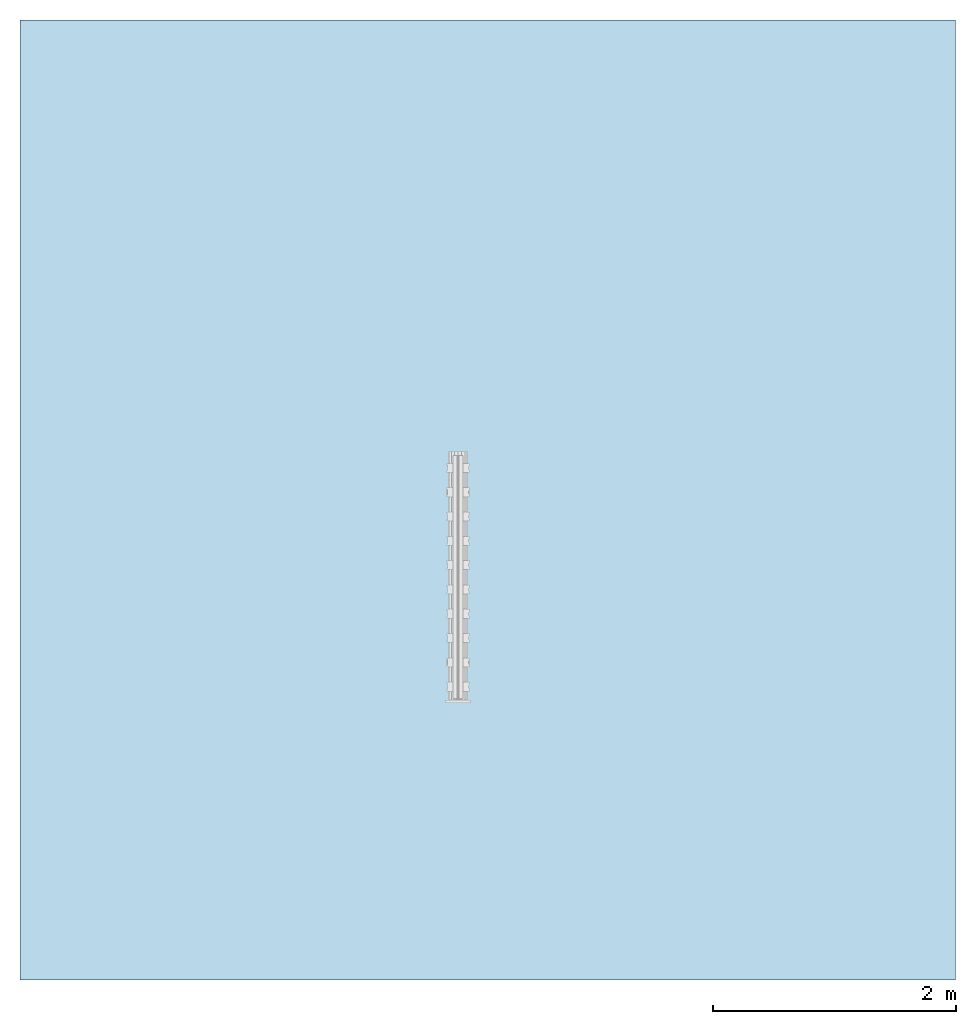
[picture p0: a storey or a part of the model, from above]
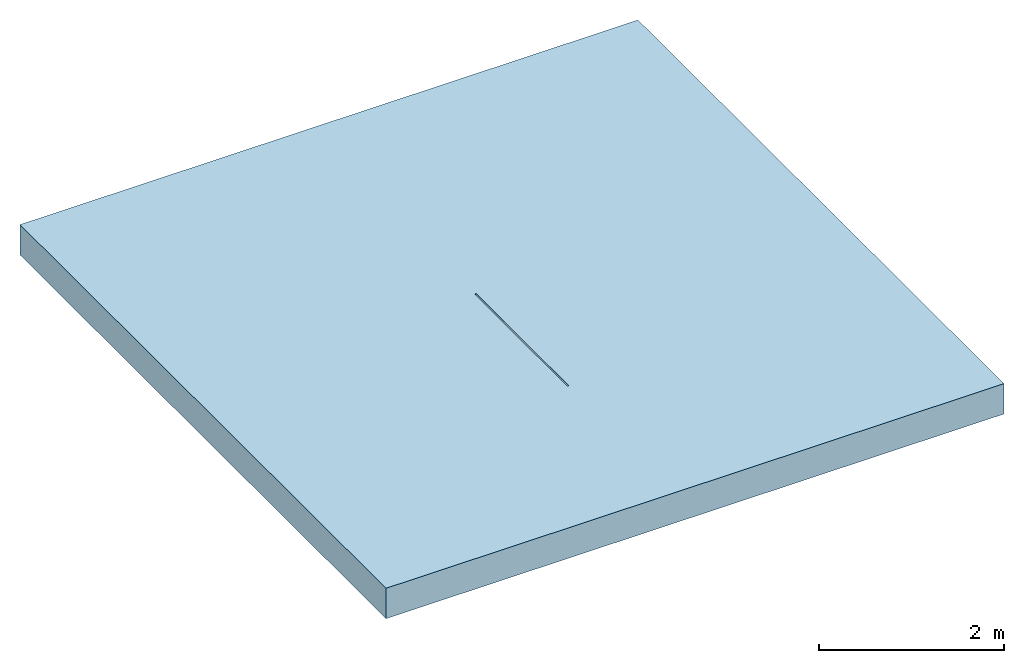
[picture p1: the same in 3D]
Properties of the parts of a building model (IFC2X3)

# File
Description: ViewDefinition [CoordinationView]
File name: 32994 - Q-Slot Edge - G.S.ifc
Time: 2013-08-14T09:29:20
Written by: Autodesk Revit 2013
Made in: 20120221_2030(x64)

# IfcProject, Project Number
LongName: Project Name; Phase: Project Status

# IfcSite, Default
RefLatitude: 42, 21, 30, 344238; RefLongitude: -71, -3, -35, -194702; RefElevation: 0 mm

# IfcBuilding
Pset_BuildingCommon - NumberOfStoreys: 1
Other - Project Issue Date: Issue Date; Project Number: Project Number; Project Address: ## Street City, State Zip; Client Name: Owner; Project Status: Project Status; Project Name: Project Name

# IfcBuildingStorey, Level 1
LongName: Level 1; Elevation: 0 mm
Constraints - Elevation Base: 0; Elevation: 0 mm
Graphics - Symbol at End 1 Default: no; Symbol at End 2 Default: yes; Line Weight: 1; Line Pattern: Center; Symbol: M_Level Head - Circle: M_Level Head - Circle; Color: 0
Identity Data - Name: Level 1; Structural: no; Building Story: yes
Dimensions - Computation Height: 0 mm

# IfcFlowTerminal: 32994 - Q-Slot Edge - G.S, Qmax 150:32994 - Q-Slot Edge - G.S:32994 - Q-Slot Edge - G.S:730922
In: Level 1
Identity Data - Mark: 77; Type Comments: ACO Qmax 150 channel assembly complete with ACO Q-Slot galvanised steel edge rail; Cost: 0; Price: POA - contact ACO; Maintenance Guidelines: http://www.aco.co.uk/download.php?id=220; Product Brochure: http://www.aco.co.uk/download.php?id=220; Assembly Description: Rain Water Drainage; Installation Guidelines: http://www.aco.co.uk/download.php?id=220; Fax: +44 (0)1462 815895; Product Code: 32994; e-mail Sales: customersupport@aco.co.uk; Model Description: High capacity slot drainage channel system; Address: ACO Business Park, Hitchin Road, Shefford, Bedfordshire, United Kingdom SG17 5TE; Telephone: +44 (0)1462 816666; Assembly Code: D2040; OmniClass Title: Rainwater Removal; Model: ACO Qmax 150; Product Page URL: http://www.aco.co.uk/product_detail.php?id=79; URL: www.aco.co.uk; e-mail Technical: technical@aco.co.uk; Manufacturer: ACO Technologies plc - ACO Water Management Division; OmniClass Number: 23.70.50.24
Constraints - Level: Level: Level 1; Moves With Nearby Elements: no
Phasing - Phase Created: New Construction
Construction - 32997_150 End Cap (at Male end): no; 32997_150 End Cap (at Female end): no; V_CoarseE1: no; E5-QSlot-GalvSteel: yes; E4-QGuard-GalvSteel: no; E1-QFlow-DuctileIron: no; E2-QGuard-DuctileIron: no; V_Coarse_E5: yes; E3-QFlow-GalvSteel: no
Materials and Finishes - Channel Material: Medium Density Polyethylene; Channel Colour: Black; Seal Material: Chloroprene; Edge Rail Material: Steel; Seal Colour: Black; Edge Rail Colour: Silver; Edge Rail Finish: Galvanised
General - TagNumber: 0; SerialNumber: 0
Data - Hydraulic Performance: http://www.aco.co.uk/download.php?id=220; Product Dimensions: 2000mm x 210mm x 500mm (LxWxH); Channel C.S.A: 17671mm²; Concrete Surround Volume - Load Class E 600: 0.205 m³/m; Product Standard: BS EN 1433:2002 CE marked; Invert Depth: 450mm; Load Class: A 15 - F 900; Installation - Concrete Grade: Refer to brochure; Drainage Slot Intake Area: 10000mm²/m; Concrete Surround Volume - Load Class F 900: 0.285 m³/m; Installation - Reinforcement Details: Refer to brochure; ACO Hydraulic Design Software: http://www.acodesign.co.uk; Drainage Slot Width: 10mm; Concrete Surround Volume - Load Class A 15 - D 400: 0.135 m³/m; Product Weight: 20.9kg
Model Properties - Multi-Functional End Cap - Weight: 1 kg; Multi-Functional End Cap - Seal Material: Chloroprene; Multi-Functional End Cap - Dimensions: Ø210mm x 240mm (ØxL); Multi-Functional End Cap - Product Code: 32997; Multi-Functional End Cap - Seal Recycled Material Content: 0%; Multi-Functional End Cap - Seal Recyclable: Fully recyclable; Multi-Functional End Cap - Channel Recycled Material Content: Variable %; Multi-Functional End Cap - Model Description: High capacity slot drainage channel system; Multi-Functional End Cap - Channel Colour: Black; Multi-Functional End Cap - Channel Recyclable: Fully recyclable; Multi-Functional End Cap - Seal Colour: Black; Multi-Functional End Cap - Channel Material: Medium Density Polyethylene
Dimensions - Depth Overall: 500 mm; Floor Opening Width: 18 mm; Width Overall: 210 mm; Length: 2000 mm; TopCoarse: 113 mm; BoreCentre: 377 mm
Green Building Properties - Edge Rail Recyclable: Fully recyclable; Seal Recyclable: Fully recyclable; Channel Recycled Material Content: Variable %; Channel Recyclable: Fully recyclable; Seal Recycled Material Content: 0%; Edge Rail Recycled Material Content: Between 40% - 90%
Other - Revision: 1; Created by: www.aco.co.uk

# IfcOpeningElement: Opening
In: Level 1
Dimensions - Volume: 24171080000 mm3; Area: 60794000 mm2; Perimeter: 31200 mm; Thickness: 400 mm
Constraints - Room Bounding: yes; Related to Mass: no; Level: Level: Level 1; Height Offset From Level: 0 mm
Phasing - Phase Created: New Construction
Structural - Structural: no; Enable Analytical Model: no
Analytical Properties - Roughness: 1; Absorptance: 0.1
Graphics - Coarse Scale Fill Color: 0
Construction - Default Thickness: 400 mm; Function: 0
Materials and Finishes - Structural Material: Plant

# IfcSlab: Floor:Generic Floor - 400mm, Floor:Generic Floor - 400mm:193825
In: Level 1
PredefinedType: FLOOR; Material: Plant 400 mm
Dimensions - Volume: 24171080000 mm3; Area: 60794000 mm2; Perimeter: 31200 mm; Thickness: 400 mm
Constraints - Room Bounding: yes; Related to Mass: no; Level: Level: Level 1; Height Offset From Level: 0 mm
Phasing - Phase Created: New Construction
Structural - Structural: no; Enable Analytical Model: no
Pset_SlabCommon - Reference: Generic Floor - 400mm; IsExternal: no; LoadBearing: yes
Analytical Properties - Roughness: 1; Absorptance: 0.1
Graphics - Coarse Scale Fill Color: 0
Construction - Default Thickness: 400 mm; Function: 0
Materials and Finishes - Structural Material: Plant
